One B-rep face of a CAD part: STEP entity #17.
In plain terms, the planar face has unit normal (-1, 0, 0).
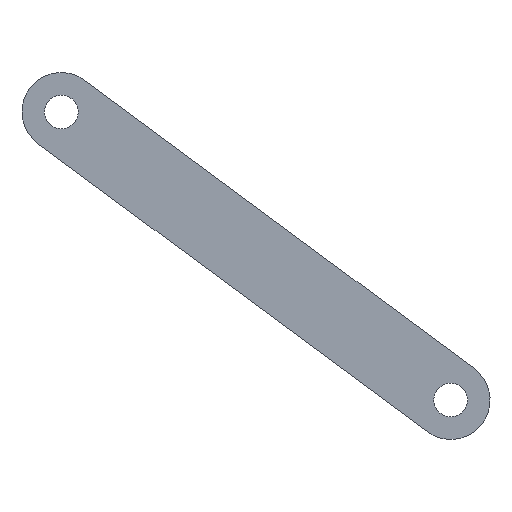
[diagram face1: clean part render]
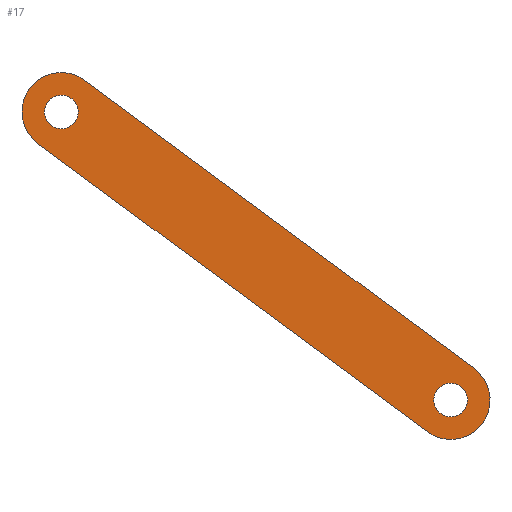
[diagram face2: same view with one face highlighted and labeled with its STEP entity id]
Its self-contained STEP definition (entity closure, numbers rounded to 3 decimals):
#17 = ADVANCED_FACE('',(#18,#143,#174),#32,.F.);
#18 = FACE_BOUND('',#19,.F.);
#19 = EDGE_LOOP('',(#20,#55,#84,#112));
#20 = ORIENTED_EDGE('',*,*,#21,.F.);
#21 = EDGE_CURVE('',#22,#24,#26,.T.);
#22 = VERTEX_POINT('',#23);
#23 = CARTESIAN_POINT('',(20.4,119.834,0.151));
#24 = VERTEX_POINT('',#25);
#25 = CARTESIAN_POINT('',(20.4,147.534,20.651));
#26 = SURFACE_CURVE('',#27,(#31,#43),.PCURVE_S1.);
#27 = LINE('',#28,#29);
#28 = CARTESIAN_POINT('',(20.4,119.834,0.151));
#29 = VECTOR('',#30,1.);
#30 = DIRECTION('',(0.,0.804,0.595));
#31 = PCURVE('',#32,#37);
#32 = PLANE('',#33);
#33 = AXIS2_PLACEMENT_3D('',#34,#35,#36);
#34 = CARTESIAN_POINT('',(20.4,121.5,-2.1));
#35 = DIRECTION('',(1.,0.,0.));
#36 = DIRECTION('',(-0.,0.,1.));
#37 = DEFINITIONAL_REPRESENTATION('',(#38),#42);
#38 = LINE('',#39,#40);
#39 = CARTESIAN_POINT('',(2.251,1.666));
#40 = VECTOR('',#41,1.);
#41 = DIRECTION('',(0.595,-0.804));
#42 = ( GEOMETRIC_REPRESENTATION_CONTEXT(2) 
PARAMETRIC_REPRESENTATION_CONTEXT() REPRESENTATION_CONTEXT('2D SPACE',''
  ) );
#43 = PCURVE('',#44,#49);
#44 = PLANE('',#45);
#45 = AXIS2_PLACEMENT_3D('',#46,#47,#48);
#46 = CARTESIAN_POINT('',(20.4,119.834,0.151));
#47 = DIRECTION('',(0.,-0.595,0.804));
#48 = DIRECTION('',(1.,0.,0.));
#49 = DEFINITIONAL_REPRESENTATION('',(#50),#54);
#50 = LINE('',#51,#52);
#51 = CARTESIAN_POINT('',(0.,0.));
#52 = VECTOR('',#53,1.);
#53 = DIRECTION('',(0.,1.));
#54 = ( GEOMETRIC_REPRESENTATION_CONTEXT(2) 
PARAMETRIC_REPRESENTATION_CONTEXT() REPRESENTATION_CONTEXT('2D SPACE',''
  ) );
#55 = ORIENTED_EDGE('',*,*,#56,.T.);
#56 = EDGE_CURVE('',#22,#57,#59,.T.);
#57 = VERTEX_POINT('',#58);
#58 = CARTESIAN_POINT('',(20.4,123.166,-4.351));
#59 = SURFACE_CURVE('',#60,(#65,#72),.PCURVE_S1.);
#60 = CIRCLE('',#61,2.8);
#61 = AXIS2_PLACEMENT_3D('',#62,#63,#64);
#62 = CARTESIAN_POINT('',(20.4,121.5,-2.1));
#63 = DIRECTION('',(1.,0.,0.));
#64 = DIRECTION('',(-0.,0.,1.));
#65 = PCURVE('',#32,#66);
#66 = DEFINITIONAL_REPRESENTATION('',(#67),#71);
#67 = CIRCLE('',#68,2.8);
#68 = AXIS2_PLACEMENT_2D('',#69,#70);
#69 = CARTESIAN_POINT('',(0.,0.));
#70 = DIRECTION('',(1.,0.));
#71 = ( GEOMETRIC_REPRESENTATION_CONTEXT(2) 
PARAMETRIC_REPRESENTATION_CONTEXT() REPRESENTATION_CONTEXT('2D SPACE',''
  ) );
#72 = PCURVE('',#73,#78);
#73 = CYLINDRICAL_SURFACE('',#74,2.8);
#74 = AXIS2_PLACEMENT_3D('',#75,#76,#77);
#75 = CARTESIAN_POINT('',(20.4,121.5,-2.1));
#76 = DIRECTION('',(1.,0.,0.));
#77 = DIRECTION('',(-0.,0.,1.));
#78 = DEFINITIONAL_REPRESENTATION('',(#79),#83);
#79 = LINE('',#80,#81);
#80 = CARTESIAN_POINT('',(0.,0.));
#81 = VECTOR('',#82,1.);
#82 = DIRECTION('',(1.,0.));
#83 = ( GEOMETRIC_REPRESENTATION_CONTEXT(2) 
PARAMETRIC_REPRESENTATION_CONTEXT() REPRESENTATION_CONTEXT('2D SPACE',''
  ) );
#84 = ORIENTED_EDGE('',*,*,#85,.T.);
#85 = EDGE_CURVE('',#57,#86,#88,.T.);
#86 = VERTEX_POINT('',#87);
#87 = CARTESIAN_POINT('',(20.4,150.866,16.149));
#88 = SURFACE_CURVE('',#89,(#93,#100),.PCURVE_S1.);
#89 = LINE('',#90,#91);
#90 = CARTESIAN_POINT('',(20.4,123.166,-4.351));
#91 = VECTOR('',#92,1.);
#92 = DIRECTION('',(0.,0.804,0.595));
#93 = PCURVE('',#32,#94);
#94 = DEFINITIONAL_REPRESENTATION('',(#95),#99);
#95 = LINE('',#96,#97);
#96 = CARTESIAN_POINT('',(-2.251,-1.666));
#97 = VECTOR('',#98,1.);
#98 = DIRECTION('',(0.595,-0.804));
#99 = ( GEOMETRIC_REPRESENTATION_CONTEXT(2) 
PARAMETRIC_REPRESENTATION_CONTEXT() REPRESENTATION_CONTEXT('2D SPACE',''
  ) );
#100 = PCURVE('',#101,#106);
#101 = PLANE('',#102);
#102 = AXIS2_PLACEMENT_3D('',#103,#104,#105);
#103 = CARTESIAN_POINT('',(20.4,123.166,-4.351));
#104 = DIRECTION('',(0.,-0.595,0.804));
#105 = DIRECTION('',(1.,0.,0.));
#106 = DEFINITIONAL_REPRESENTATION('',(#107),#111);
#107 = LINE('',#108,#109);
#108 = CARTESIAN_POINT('',(0.,0.));
#109 = VECTOR('',#110,1.);
#110 = DIRECTION('',(0.,1.));
#111 = ( GEOMETRIC_REPRESENTATION_CONTEXT(2) 
PARAMETRIC_REPRESENTATION_CONTEXT() REPRESENTATION_CONTEXT('2D SPACE',''
  ) );
#112 = ORIENTED_EDGE('',*,*,#113,.F.);
#113 = EDGE_CURVE('',#24,#86,#114,.T.);
#114 = SURFACE_CURVE('',#115,(#120,#131),.PCURVE_S1.);
#115 = CIRCLE('',#116,2.8);
#116 = AXIS2_PLACEMENT_3D('',#117,#118,#119);
#117 = CARTESIAN_POINT('',(20.4,149.2,18.4));
#118 = DIRECTION('',(-1.,0.,0.));
#119 = DIRECTION('',(0.,-0.595,0.804));
#120 = PCURVE('',#32,#121);
#121 = DEFINITIONAL_REPRESENTATION('',(#122),#130);
#122 = ( BOUNDED_CURVE() B_SPLINE_CURVE(2,(#123,#124,#125,#126,#127,#128
,#129),.UNSPECIFIED.,.T.,.F.) B_SPLINE_CURVE_WITH_KNOTS((1,2,2,2,2,1),(
    -2.094,0.,2.094,4.189,6.283,
8.378),.UNSPECIFIED.) CURVE() GEOMETRIC_REPRESENTATION_ITEM() 
RATIONAL_B_SPLINE_CURVE((1.,0.5,1.,0.5,1.,0.5,1.)) REPRESENTATION_ITEM(
  '') );
#123 = CARTESIAN_POINT('',(22.751,-26.034));
#124 = CARTESIAN_POINT('',(25.636,-29.933));
#125 = CARTESIAN_POINT('',(20.817,-30.482));
#126 = CARTESIAN_POINT('',(15.999,-31.031));
#127 = CARTESIAN_POINT('',(17.932,-26.584));
#128 = CARTESIAN_POINT('',(19.866,-22.136));
#129 = CARTESIAN_POINT('',(22.751,-26.034));
#130 = ( GEOMETRIC_REPRESENTATION_CONTEXT(2) 
PARAMETRIC_REPRESENTATION_CONTEXT() REPRESENTATION_CONTEXT('2D SPACE',''
  ) );
#131 = PCURVE('',#132,#137);
#132 = CYLINDRICAL_SURFACE('',#133,2.8);
#133 = AXIS2_PLACEMENT_3D('',#134,#135,#136);
#134 = CARTESIAN_POINT('',(20.4,149.2,18.4));
#135 = DIRECTION('',(1.,0.,0.));
#136 = DIRECTION('',(-0.,0.,1.));
#137 = DEFINITIONAL_REPRESENTATION('',(#138),#142);
#138 = LINE('',#139,#140);
#139 = CARTESIAN_POINT('',(6.92,0.));
#140 = VECTOR('',#141,1.);
#141 = DIRECTION('',(-1.,-0.));
#142 = ( GEOMETRIC_REPRESENTATION_CONTEXT(2) 
PARAMETRIC_REPRESENTATION_CONTEXT() REPRESENTATION_CONTEXT('2D SPACE',''
  ) );
#143 = FACE_BOUND('',#144,.F.);
#144 = EDGE_LOOP('',(#145));
#145 = ORIENTED_EDGE('',*,*,#146,.F.);
#146 = EDGE_CURVE('',#147,#147,#149,.T.);
#147 = VERTEX_POINT('',#148);
#148 = CARTESIAN_POINT('',(20.4,149.2,19.6));
#149 = SURFACE_CURVE('',#150,(#155,#162),.PCURVE_S1.);
#150 = CIRCLE('',#151,1.2);
#151 = AXIS2_PLACEMENT_3D('',#152,#153,#154);
#152 = CARTESIAN_POINT('',(20.4,149.2,18.4));
#153 = DIRECTION('',(1.,0.,0.));
#154 = DIRECTION('',(-0.,0.,1.));
#155 = PCURVE('',#32,#156);
#156 = DEFINITIONAL_REPRESENTATION('',(#157),#161);
#157 = CIRCLE('',#158,1.2);
#158 = AXIS2_PLACEMENT_2D('',#159,#160);
#159 = CARTESIAN_POINT('',(20.5,-27.7));
#160 = DIRECTION('',(1.,0.));
#161 = ( GEOMETRIC_REPRESENTATION_CONTEXT(2) 
PARAMETRIC_REPRESENTATION_CONTEXT() REPRESENTATION_CONTEXT('2D SPACE',''
  ) );
#162 = PCURVE('',#163,#168);
#163 = CYLINDRICAL_SURFACE('',#164,1.2);
#164 = AXIS2_PLACEMENT_3D('',#165,#166,#167);
#165 = CARTESIAN_POINT('',(20.2,149.2,18.4));
#166 = DIRECTION('',(1.,0.,0.));
#167 = DIRECTION('',(-0.,0.,1.));
#168 = DEFINITIONAL_REPRESENTATION('',(#169),#173);
#169 = LINE('',#170,#171);
#170 = CARTESIAN_POINT('',(0.,0.2));
#171 = VECTOR('',#172,1.);
#172 = DIRECTION('',(1.,0.));
#173 = ( GEOMETRIC_REPRESENTATION_CONTEXT(2) 
PARAMETRIC_REPRESENTATION_CONTEXT() REPRESENTATION_CONTEXT('2D SPACE',''
  ) );
#174 = FACE_BOUND('',#175,.F.);
#175 = EDGE_LOOP('',(#176));
#176 = ORIENTED_EDGE('',*,*,#177,.F.);
#177 = EDGE_CURVE('',#178,#178,#180,.T.);
#178 = VERTEX_POINT('',#179);
#179 = CARTESIAN_POINT('',(20.4,121.5,-0.9));
#180 = SURFACE_CURVE('',#181,(#186,#193),.PCURVE_S1.);
#181 = CIRCLE('',#182,1.2);
#182 = AXIS2_PLACEMENT_3D('',#183,#184,#185);
#183 = CARTESIAN_POINT('',(20.4,121.5,-2.1));
#184 = DIRECTION('',(1.,0.,0.));
#185 = DIRECTION('',(-0.,0.,1.));
#186 = PCURVE('',#32,#187);
#187 = DEFINITIONAL_REPRESENTATION('',(#188),#192);
#188 = CIRCLE('',#189,1.2);
#189 = AXIS2_PLACEMENT_2D('',#190,#191);
#190 = CARTESIAN_POINT('',(0.,0.));
#191 = DIRECTION('',(1.,0.));
#192 = ( GEOMETRIC_REPRESENTATION_CONTEXT(2) 
PARAMETRIC_REPRESENTATION_CONTEXT() REPRESENTATION_CONTEXT('2D SPACE',''
  ) );
#193 = PCURVE('',#194,#199);
#194 = CYLINDRICAL_SURFACE('',#195,1.2);
#195 = AXIS2_PLACEMENT_3D('',#196,#197,#198);
#196 = CARTESIAN_POINT('',(20.2,121.5,-2.1));
#197 = DIRECTION('',(1.,0.,0.));
#198 = DIRECTION('',(-0.,0.,1.));
#199 = DEFINITIONAL_REPRESENTATION('',(#200),#204);
#200 = LINE('',#201,#202);
#201 = CARTESIAN_POINT('',(0.,0.2));
#202 = VECTOR('',#203,1.);
#203 = DIRECTION('',(1.,0.));
#204 = ( GEOMETRIC_REPRESENTATION_CONTEXT(2) 
PARAMETRIC_REPRESENTATION_CONTEXT() REPRESENTATION_CONTEXT('2D SPACE',''
  ) );
